VERSION 5.7 ;
  NOWIREEXTENSIONATPIN ON ;
  DIVIDERCHAR "/" ;
  BUSBITCHARS "[]" ;
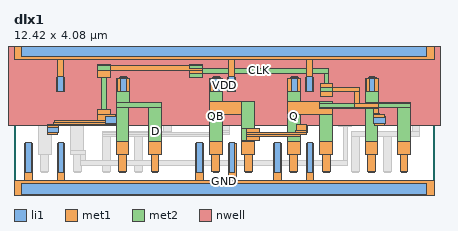
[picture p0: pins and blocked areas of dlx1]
MACRO dlx1
  CLASS BLOCK ;
  FOREIGN dlx1 ;
  ORIGIN 0.000 0.000 ;
  SIZE 12.420 BY 4.080 ;
  PIN CLK
    ANTENNAGATEAREA 0.882000 ;
    PORT
      LAYER li1 ;
        RECT 2.700 1.940 3.030 2.130 ;
        RECT 10.645 1.940 10.975 2.130 ;
        RECT 0.985 1.660 1.315 1.850 ;
      LAYER met1 ;
        RECT 2.470 3.640 2.850 3.690 ;
        RECT 5.200 3.640 5.580 3.690 ;
        RECT 2.470 3.500 5.580 3.640 ;
        RECT 2.470 3.310 2.850 3.500 ;
        RECT 5.200 3.310 5.580 3.500 ;
        RECT 9.050 3.010 9.430 3.130 ;
        RECT 9.050 2.870 10.220 3.010 ;
        RECT 9.050 2.750 9.430 2.870 ;
        RECT 10.080 2.520 10.220 2.870 ;
        RECT 10.080 2.380 10.780 2.520 ;
        RECT 2.470 2.200 2.850 2.360 ;
        RECT 10.640 2.240 10.780 2.380 ;
        RECT 10.640 2.200 10.800 2.240 ;
        RECT 2.470 2.030 3.015 2.200 ;
        RECT 10.640 2.100 10.960 2.200 ;
        RECT 1.190 1.960 3.015 2.030 ;
        RECT 1.160 1.920 3.015 1.960 ;
        RECT 1.000 1.890 3.015 1.920 ;
        RECT 1.000 1.820 1.330 1.890 ;
        RECT 2.715 1.870 3.015 1.890 ;
        RECT 10.660 1.870 10.960 2.100 ;
        RECT 1.000 1.600 1.300 1.820 ;
      LAYER met2 ;
        RECT 2.470 3.310 2.850 3.690 ;
        RECT 5.200 3.570 5.580 3.690 ;
        RECT 5.200 3.430 9.310 3.570 ;
        RECT 5.200 3.310 5.580 3.430 ;
        RECT 2.590 2.360 2.730 3.310 ;
        RECT 9.170 3.130 9.310 3.430 ;
        RECT 9.050 2.750 9.430 3.130 ;
        RECT 2.470 1.980 2.850 2.360 ;
    END
  END CLK
  PIN D
    ANTENNADIFFAREA 0.659400 ;
    PORT
      LAYER li1 ;
        RECT 3.145 2.870 3.315 3.330 ;
        RECT 3.125 0.490 3.295 1.370 ;
        RECT 4.085 0.490 4.255 1.370 ;
      LAYER met1 ;
        RECT 3.115 3.260 3.345 3.310 ;
        RECT 3.050 2.880 3.410 3.260 ;
        RECT 3.020 1.010 3.400 1.390 ;
        RECT 3.980 1.010 4.360 1.390 ;
        RECT 3.095 0.510 3.325 1.010 ;
        RECT 4.055 0.510 4.285 1.010 ;
      LAYER met2 ;
        RECT 3.040 2.560 3.420 3.260 ;
        RECT 3.020 2.400 4.360 2.560 ;
        RECT 3.020 1.010 3.400 2.400 ;
        RECT 3.980 1.010 4.360 2.400 ;
    END
  END D
  PIN QB
    ANTENNAGATEAREA 0.441000 ;
    ANTENNADIFFAREA 0.659400 ;
    PORT
      LAYER li1 ;
        RECT 5.905 2.870 6.075 3.330 ;
        RECT 8.345 1.660 8.675 1.850 ;
        RECT 5.885 0.490 6.055 1.370 ;
        RECT 6.845 0.490 7.015 1.370 ;
      LAYER met1 ;
        RECT 5.875 3.260 6.105 3.310 ;
        RECT 5.800 2.880 6.160 3.260 ;
        RECT 5.780 2.210 7.120 2.590 ;
        RECT 6.880 1.680 7.260 1.800 ;
        RECT 8.360 1.740 8.660 1.920 ;
        RECT 8.330 1.680 8.660 1.740 ;
        RECT 6.880 1.600 8.660 1.680 ;
        RECT 6.880 1.540 8.470 1.600 ;
        RECT 6.880 1.420 7.260 1.540 ;
        RECT 6.880 1.390 7.120 1.420 ;
        RECT 5.780 1.010 6.160 1.390 ;
        RECT 6.740 1.010 7.120 1.390 ;
        RECT 5.855 0.510 6.085 1.010 ;
        RECT 6.815 0.510 7.045 1.010 ;
      LAYER met2 ;
        RECT 5.780 1.010 6.170 3.260 ;
        RECT 6.740 1.800 7.120 2.590 ;
        RECT 6.740 1.420 7.260 1.800 ;
        RECT 6.740 1.010 7.120 1.420 ;
    END
  END QB
  PIN Q
    ANTENNADIFFAREA 1.318800 ;
    PORT
      LAYER li1 ;
        RECT 8.205 2.870 8.375 3.330 ;
        RECT 10.505 2.870 10.675 3.330 ;
        RECT 8.185 0.490 8.355 1.370 ;
        RECT 9.145 0.490 9.315 1.370 ;
        RECT 10.485 0.490 10.655 1.370 ;
        RECT 11.445 0.490 11.615 1.370 ;
      LAYER met1 ;
        RECT 8.175 3.260 8.405 3.310 ;
        RECT 10.475 3.260 10.705 3.310 ;
        RECT 8.100 2.880 8.460 3.260 ;
        RECT 10.410 2.880 10.770 3.260 ;
        RECT 8.080 2.210 9.420 2.590 ;
        RECT 8.080 1.010 8.460 1.390 ;
        RECT 9.040 1.010 9.420 1.390 ;
        RECT 10.380 1.010 10.760 1.390 ;
        RECT 11.340 1.010 11.720 1.390 ;
        RECT 8.155 0.510 8.385 1.010 ;
        RECT 9.115 0.510 9.345 1.010 ;
        RECT 10.455 0.510 10.685 1.010 ;
        RECT 11.415 0.510 11.645 1.010 ;
      LAYER met2 ;
        RECT 8.080 1.010 8.470 3.260 ;
        RECT 9.040 2.520 9.420 2.590 ;
        RECT 10.400 2.560 10.780 3.260 ;
        RECT 10.380 2.520 11.720 2.560 ;
        RECT 9.040 2.400 11.720 2.520 ;
        RECT 9.040 2.380 10.760 2.400 ;
        RECT 9.040 1.010 9.420 2.380 ;
        RECT 10.380 1.010 10.760 2.380 ;
        RECT 11.340 1.010 11.720 2.400 ;
    END
  END Q
  PIN VDD
    ANTENNADIFFAREA 3.862800 ;
    PORT
      LAYER nwell ;
        RECT -0.230 1.870 12.650 4.410 ;
      LAYER li1 ;
        RECT 0.210 3.915 12.210 4.245 ;
        RECT 1.285 2.870 1.455 3.330 ;
        RECT 6.345 2.870 6.515 3.330 ;
        RECT 8.645 2.870 8.815 3.330 ;
      LAYER met1 ;
        RECT 0.000 3.840 12.420 4.320 ;
        RECT 1.285 3.310 1.455 3.840 ;
        RECT 6.345 3.310 6.515 3.840 ;
        RECT 8.645 3.310 8.815 3.840 ;
        RECT 1.255 2.890 1.485 3.310 ;
        RECT 6.315 2.890 6.545 3.310 ;
        RECT 8.615 2.890 8.845 3.310 ;
    END
  END VDD
  PIN GND
    ANTENNADIFFAREA 5.110200 ;
    PORT
      LAYER li1 ;
        RECT 0.345 0.490 0.515 1.370 ;
        RECT 1.305 0.490 1.475 1.370 ;
        RECT 5.405 0.490 5.575 1.370 ;
        RECT 6.365 0.490 6.535 1.370 ;
        RECT 7.705 0.490 7.875 1.370 ;
        RECT 8.665 0.490 8.835 1.370 ;
        RECT 0.210 -0.165 12.210 0.165 ;
      LAYER met1 ;
        RECT 0.315 0.240 0.545 1.350 ;
        RECT 1.275 0.240 1.505 1.350 ;
        RECT 5.375 0.240 5.605 1.350 ;
        RECT 6.335 0.240 6.565 1.350 ;
        RECT 7.675 0.240 7.905 1.350 ;
        RECT 8.635 0.240 8.865 1.350 ;
        RECT 0.000 -0.240 12.420 0.240 ;
    END
  END GND
  OBS
      LAYER li1 ;
        RECT 0.845 2.870 1.015 3.330 ;
        RECT 3.585 2.870 3.755 3.330 ;
        RECT 10.945 2.870 11.115 3.330 ;
        RECT 3.285 1.940 3.615 2.130 ;
        RECT 10.060 1.940 10.390 2.130 ;
        RECT 6.045 1.660 6.375 1.850 ;
        RECT 0.825 0.490 0.995 1.370 ;
        RECT 1.785 0.490 1.955 1.370 ;
        RECT 2.645 0.490 2.815 1.370 ;
        RECT 3.605 0.490 3.775 1.370 ;
        RECT 10.005 0.490 10.175 1.370 ;
        RECT 10.965 0.490 11.135 1.370 ;
      LAYER met1 ;
        RECT 9.470 3.640 9.850 3.690 ;
        RECT 9.470 3.500 11.060 3.640 ;
        RECT 9.470 3.310 9.850 3.500 ;
        RECT 10.920 3.310 11.060 3.500 ;
        RECT 0.815 3.260 1.045 3.310 ;
        RECT 0.740 2.880 1.100 3.260 ;
        RECT 3.555 3.200 3.785 3.310 ;
        RECT 10.915 3.200 11.145 3.310 ;
        RECT 3.555 3.130 4.645 3.200 ;
        RECT 3.555 3.000 5.160 3.130 ;
        RECT 3.555 2.890 3.785 3.000 ;
        RECT 4.425 2.750 5.160 3.000 ;
        RECT 10.915 3.000 12.005 3.200 ;
        RECT 10.915 2.890 11.145 3.000 ;
        RECT 1.920 2.590 3.430 2.660 ;
        RECT 0.720 2.520 3.430 2.590 ;
        RECT 0.720 2.210 2.060 2.520 ;
        RECT 3.290 2.240 3.430 2.520 ;
        RECT 3.290 2.200 3.440 2.240 ;
        RECT 3.290 2.100 3.600 2.200 ;
        RECT 3.300 1.870 3.600 2.100 ;
        RECT 4.425 1.690 4.645 2.750 ;
        RECT 9.610 2.200 9.990 2.220 ;
        RECT 6.060 1.740 6.360 1.920 ;
        RECT 9.610 1.870 10.375 2.200 ;
        RECT 9.610 1.840 9.990 1.870 ;
        RECT 2.615 1.680 4.645 1.690 ;
        RECT 6.020 1.680 6.360 1.740 ;
        RECT 11.785 1.690 12.005 3.000 ;
        RECT 2.615 1.600 6.360 1.680 ;
        RECT 2.615 1.540 6.160 1.600 ;
        RECT 9.975 1.540 12.005 1.690 ;
        RECT 0.720 1.010 1.100 1.390 ;
        RECT 1.680 1.010 2.060 1.390 ;
        RECT 0.795 0.510 1.025 1.010 ;
        RECT 1.755 0.510 1.985 1.010 ;
        RECT 2.615 0.510 2.845 1.540 ;
        RECT 3.575 0.510 3.805 1.540 ;
        RECT 9.975 0.510 10.205 1.540 ;
        RECT 10.935 0.510 11.165 1.540 ;
      LAYER met2 ;
        RECT 4.900 3.850 9.730 3.990 ;
        RECT 0.720 1.010 1.110 3.260 ;
        RECT 4.900 3.130 5.040 3.850 ;
        RECT 9.590 3.690 9.730 3.850 ;
        RECT 9.470 3.310 9.850 3.690 ;
        RECT 4.780 2.750 5.160 3.130 ;
        RECT 1.680 1.150 2.060 2.590 ;
        RECT 9.610 1.840 9.990 2.220 ;
        RECT 1.680 1.010 2.100 1.150 ;
        RECT 1.960 0.840 2.100 1.010 ;
        RECT 9.730 0.840 9.870 1.840 ;
        RECT 1.960 0.700 9.870 0.840 ;
  END
END dlx1
END LIBRARY

